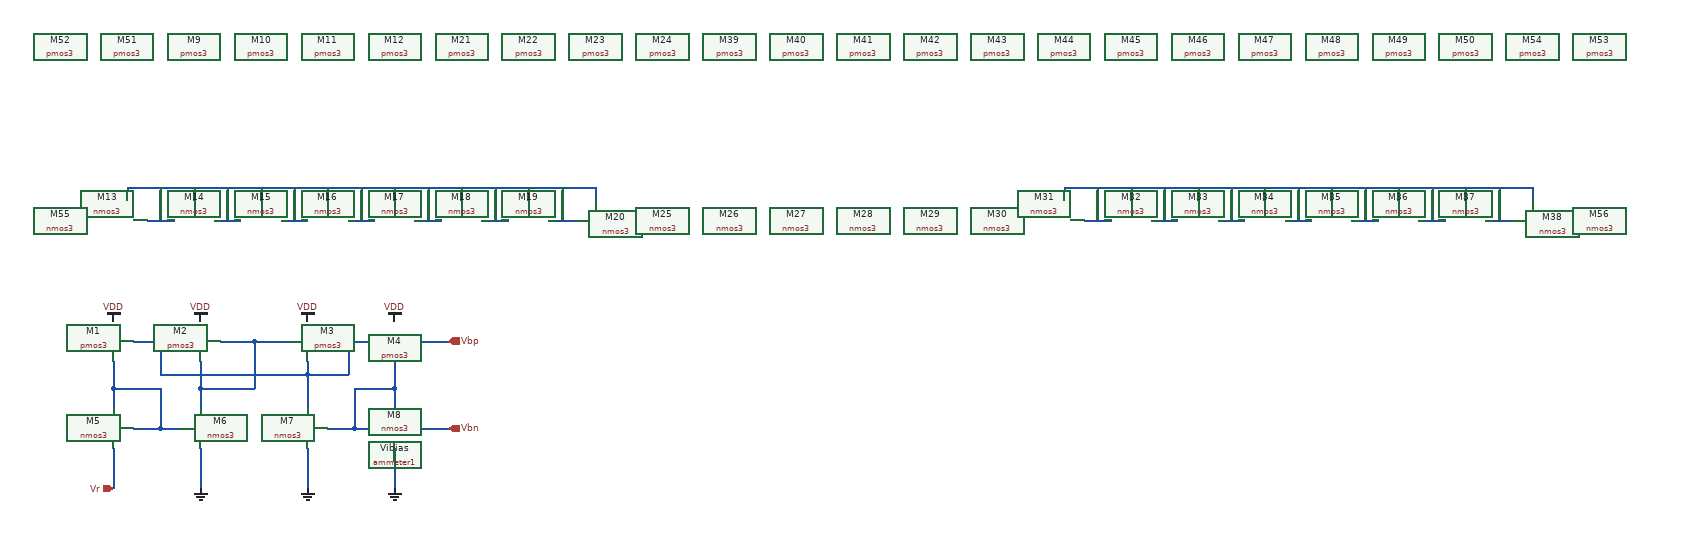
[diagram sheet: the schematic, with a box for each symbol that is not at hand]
v {xschem version=2.9.9 file_version=1.2 }
G {}
K {}
V {}
S {}
E {}
N 250 20 250 80 { lab=GND}
N 410 20 410 80 { lab=GND}
N 250 -70 250 -40 { lab=#net1}
N 410 -90 410 -40 { lab=Vbp}
N 330 -140 380 -140 { lab=#net1}
N 330 -140 330 -70 { lab=#net1}
N 250 -70 330 -70 { lab=#net1}
N 410 -90 470 -90 { lab=Vbp}
N 470 -140 470 -90 { lab=Vbp}
N 190 -90 410 -90 { lab=Vbp}
N 190 -140 190 -90 { lab=Vbp}
N 150 -140 190 -140 { lab=Vbp}
N 120 -70 120 -40 { lab=#net2}
N 190 -10 220 -10 { lab=#net2}
N 120 -70 190 -70 { lab=#net2}
N 190 -70 190 -10 { lab=#net2}
N 540 -70 540 -40 { lab=Vbn}
N 280 -140 330 -140 { lab=#net1}
N 250 -110 250 -70 { lab=#net1}
N 410 -110 410 -90 { lab=Vbp}
N 120 -110 120 -70 { lab=#net2}
N 150 -10 190 -10 { lab=#net2}
N 480 -70 540 -70 { lab=Vbn}
N 540 -110 540 -70 { lab=Vbn}
N 480 -70 480 -10 { lab=Vbn}
N 440 -10 480 -10 { lab=Vbn}
N 120 20 120 80 { lab=Vr}
N 480 -10 510 -10 { lab=Vbn}
N 510 -10 620 -10 { lab=Vbn}
N 470 -140 510 -140 { lab=Vbp}
N 510 -140 620 -140 { lab=Vbp}
N 540 50 540 80 { lab=GND}
N 540 20 540 40 { lab=#net3}
N 140 -370 140 -350 { lab=#net8}
N 140 -370 840 -370 { lab=#net8}
N 840 -370 840 -350 { lab=#net8}
N 170 -320 210 -320 { lab=#net8}
N 270 -320 310 -320 { lab=#net8}
N 370 -320 410 -320 { lab=#net8}
N 470 -320 510 -320 { lab=#net8}
N 570 -320 610 -320 { lab=#net8}
N 670 -320 710 -320 { lab=#net8}
N 770 -320 810 -320 { lab=#net8}
N 790 -370 790 -320 { lab=#net8}
N 740 -370 740 -350 { lab=#net8}
N 640 -370 640 -350 { lab=#net8}
N 540 -370 540 -350 { lab=#net8}
N 440 -370 440 -350 { lab=#net8}
N 340 -370 340 -350 { lab=#net8}
N 240 -370 240 -350 { lab=#net8}
N 190 -370 190 -320 { lab=#net8}
N 290 -370 290 -320 { lab=#net8}
N 390 -370 390 -320 { lab=#net8}
N 490 -370 490 -320 { lab=#net8}
N 590 -370 590 -320 { lab=#net8}
N 690 -370 690 -320 { lab=#net8}
N 1540 -370 1540 -350 { lab=#net9}
N 1540 -370 2240 -370 { lab=#net9}
N 2240 -370 2240 -350 { lab=#net9}
N 1570 -320 1610 -320 { lab=#net9}
N 1670 -320 1710 -320 { lab=#net9}
N 1770 -320 1810 -320 { lab=#net9}
N 1870 -320 1910 -320 { lab=#net9}
N 1970 -320 2010 -320 { lab=#net9}
N 2070 -320 2110 -320 { lab=#net9}
N 2170 -320 2210 -320 { lab=#net9}
N 2190 -370 2190 -320 { lab=#net9}
N 2140 -370 2140 -350 { lab=#net9}
N 2040 -370 2040 -350 { lab=#net9}
N 1940 -370 1940 -350 { lab=#net9}
N 1840 -370 1840 -350 { lab=#net9}
N 1740 -370 1740 -350 { lab=#net9}
N 1640 -370 1640 -350 { lab=#net9}
N 1590 -370 1590 -320 { lab=#net9}
N 1690 -370 1690 -320 { lab=#net9}
N 1790 -370 1790 -320 { lab=#net9}
N 1890 -370 1890 -320 { lab=#net9}
N 1990 -370 1990 -320 { lab=#net9}
N 2090 -370 2090 -320 { lab=#net9}
C {madvlsi/pmos3.sym} 120 -140 0 1 {name=M1
L=1.0
W=3
body=VDD
nf=1
mult=1
ad="'int((nf+1)/2) * W/nf * 0.29'" 
pd="'2*int((nf+1)/2) * (W/nf + 0.29)'"
as="'int((nf+2)/2) * W/nf * 0.29'" 
ps="'2*int((nf+2)/2) * (W/nf + 0.29)'"
nrd="'0.29 / W'" nrs="'0.29 / W'"
sa=0 sb=0 sd=0
model=pfet_01v8
spiceprefix=X
}
C {madvlsi/pmos3.sym} 250 -140 0 1 {name=M2
L=1.0
W=3
body=VDD
nf=1
mult=1
ad="'int((nf+1)/2) * W/nf * 0.29'" 
pd="'2*int((nf+1)/2) * (W/nf + 0.29)'"
as="'int((nf+2)/2) * W/nf * 0.29'" 
ps="'2*int((nf+2)/2) * (W/nf + 0.29)'"
nrd="'0.29 / W'" nrs="'0.29 / W'"
sa=0 sb=0 sd=0
model=pfet_01v8
spiceprefix=X
}
C {madvlsi/pmos3.sym} 410 -140 0 0 {name=M3
L=1.0
W=3
body=VDD
nf=1
mult=1
ad="'int((nf+1)/2) * W/nf * 0.29'" 
pd="'2*int((nf+1)/2) * (W/nf + 0.29)'"
as="'int((nf+2)/2) * W/nf * 0.29'" 
ps="'2*int((nf+2)/2) * (W/nf + 0.29)'"
nrd="'0.29 / W'" nrs="'0.29 / W'"
sa=0 sb=0 sd=0
model=pfet_01v8
spiceprefix=X
}
C {madvlsi/pmos3.sym} 540 -140 0 0 {name=M4
L=1.0
W=3
body=VDD
nf=1
mult=1
ad="'int((nf+1)/2) * W/nf * 0.29'" 
pd="'2*int((nf+1)/2) * (W/nf + 0.29)'"
as="'int((nf+2)/2) * W/nf * 0.29'" 
ps="'2*int((nf+2)/2) * (W/nf + 0.29)'"
nrd="'0.29 / W'" nrs="'0.29 / W'"
sa=0 sb=0 sd=0
model=pfet_01v8
spiceprefix=X
}
C {madvlsi/nmos3.sym} 120 -10 0 1 {name=M5
L=1.0
W=3
body=GND
nf=1
mult=8
ad="'int((nf+1)/2) * W/nf * 0.29'" 
pd="'2*int((nf+1)/2) * (W/nf + 0.29)'"
as="'int((nf+2)/2) * W/nf * 0.29'" 
ps="'2*int((nf+2)/2) * (W/nf + 0.29)'"
nrd="'0.29 / W'" nrs="'0.29 / W'"
sa=0 sb=0 sd=0
model=nfet_01v8
spiceprefix=X
}
C {madvlsi/nmos3.sym} 250 -10 0 0 {name=M6
L=1.0
W=3
body=GND
nf=1
mult=1
ad="'int((nf+1)/2) * W/nf * 0.29'" 
pd="'2*int((nf+1)/2) * (W/nf + 0.29)'"
as="'int((nf+2)/2) * W/nf * 0.29'" 
ps="'2*int((nf+2)/2) * (W/nf + 0.29)'"
nrd="'0.29 / W'" nrs="'0.29 / W'"
sa=0 sb=0 sd=0
model=nfet_01v8
spiceprefix=X
}
C {madvlsi/nmos3.sym} 410 -10 0 1 {name=M7
L=1.0
W=3
body=GND
nf=1
mult=1
ad="'int((nf+1)/2) * W/nf * 0.29'" 
pd="'2*int((nf+1)/2) * (W/nf + 0.29)'"
as="'int((nf+2)/2) * W/nf * 0.29'" 
ps="'2*int((nf+2)/2) * (W/nf + 0.29)'"
nrd="'0.29 / W'" nrs="'0.29 / W'"
sa=0 sb=0 sd=0
model=nfet_01v8
spiceprefix=X
}
C {madvlsi/nmos3.sym} 540 -10 0 0 {name=M8
L=1.0
W=3
body=GND
nf=1
mult=1
ad="'int((nf+1)/2) * W/nf * 0.29'" 
pd="'2*int((nf+1)/2) * (W/nf + 0.29)'"
as="'int((nf+2)/2) * W/nf * 0.29'" 
ps="'2*int((nf+2)/2) * (W/nf + 0.29)'"
nrd="'0.29 / W'" nrs="'0.29 / W'"
sa=0 sb=0 sd=0
model=nfet_01v8
spiceprefix=X
}
C {madvlsi/vdd.sym} 120 -170 0 0 {name=l1 lab=VDD}
C {madvlsi/vdd.sym} 250 -170 0 0 {name=l2 lab=VDD}
C {madvlsi/vdd.sym} 410 -170 0 0 {name=l3 lab=VDD}
C {madvlsi/vdd.sym} 540 -170 0 0 {name=l4 lab=VDD}
C {madvlsi/gnd.sym} 250 80 0 0 {name=l6 lab=GND}
C {madvlsi/gnd.sym} 410 80 0 0 {name=l7 lab=GND}
C {madvlsi/gnd.sym} 540 80 0 0 {name=l8 lab=GND}
C {devices/opin.sym} 620 -10 0 0 {name=p1 lab=Vbn}
C {devices/opin.sym} 620 -140 0 0 {name=p2 lab=Vbp}
C {devices/iopin.sym} 120 80 1 0 {name=p3 lab=Vr}
C {madvlsi/ammeter1.sym} 540 40 0 0 {name=Vibias}
C {madvlsi/pmos3.sym} 240 -580 1 1 {name=M9
L=1.0
W=3
body=VDD
nf=1
mult=1
ad="'int((nf+1)/2) * W/nf * 0.29'" 
pd="'2*int((nf+1)/2) * (W/nf + 0.29)'"
as="'int((nf+2)/2) * W/nf * 0.29'" 
ps="'2*int((nf+2)/2) * (W/nf + 0.29)'"
nrd="'0.29 / W'" nrs="'0.29 / W'"
sa=0 sb=0 sd=0
model=pfet_01v8
spiceprefix=X
}
C {madvlsi/pmos3.sym} 340 -580 1 1 {name=M10
L=1.0
W=3
body=VDD
nf=1
mult=1
ad="'int((nf+1)/2) * W/nf * 0.29'" 
pd="'2*int((nf+1)/2) * (W/nf + 0.29)'"
as="'int((nf+2)/2) * W/nf * 0.29'" 
ps="'2*int((nf+2)/2) * (W/nf + 0.29)'"
nrd="'0.29 / W'" nrs="'0.29 / W'"
sa=0 sb=0 sd=0
model=pfet_01v8
spiceprefix=X
}
C {madvlsi/pmos3.sym} 440 -580 1 1 {name=M11
L=1.0
W=3
body=VDD
nf=1
mult=1
ad="'int((nf+1)/2) * W/nf * 0.29'" 
pd="'2*int((nf+1)/2) * (W/nf + 0.29)'"
as="'int((nf+2)/2) * W/nf * 0.29'" 
ps="'2*int((nf+2)/2) * (W/nf + 0.29)'"
nrd="'0.29 / W'" nrs="'0.29 / W'"
sa=0 sb=0 sd=0
model=pfet_01v8
spiceprefix=X
}
C {madvlsi/pmos3.sym} 540 -580 1 1 {name=M12
L=1.0
W=3
body=VDD
nf=1
mult=1
ad="'int((nf+1)/2) * W/nf * 0.29'" 
pd="'2*int((nf+1)/2) * (W/nf + 0.29)'"
as="'int((nf+2)/2) * W/nf * 0.29'" 
ps="'2*int((nf+2)/2) * (W/nf + 0.29)'"
nrd="'0.29 / W'" nrs="'0.29 / W'"
sa=0 sb=0 sd=0
model=pfet_01v8
spiceprefix=X
}
C {madvlsi/nmos3.sym} 140 -320 1 0 {name=M13
L=1.0
W=3
body=GND
nf=1
mult=1
ad="'int((nf+1)/2) * W/nf * 0.29'" 
pd="'2*int((nf+1)/2) * (W/nf + 0.29)'"
as="'int((nf+2)/2) * W/nf * 0.29'" 
ps="'2*int((nf+2)/2) * (W/nf + 0.29)'"
nrd="'0.29 / W'" nrs="'0.29 / W'"
sa=0 sb=0 sd=0
model=nfet_01v8
spiceprefix=X
}
C {madvlsi/nmos3.sym} 240 -320 1 0 {name=M14
L=1.0
W=3
body=GND
nf=1
mult=1
ad="'int((nf+1)/2) * W/nf * 0.29'" 
pd="'2*int((nf+1)/2) * (W/nf + 0.29)'"
as="'int((nf+2)/2) * W/nf * 0.29'" 
ps="'2*int((nf+2)/2) * (W/nf + 0.29)'"
nrd="'0.29 / W'" nrs="'0.29 / W'"
sa=0 sb=0 sd=0
model=nfet_01v8
spiceprefix=X
}
C {madvlsi/nmos3.sym} 340 -320 1 0 {name=M15
L=1.0
W=3
body=GND
nf=1
mult=1
ad="'int((nf+1)/2) * W/nf * 0.29'" 
pd="'2*int((nf+1)/2) * (W/nf + 0.29)'"
as="'int((nf+2)/2) * W/nf * 0.29'" 
ps="'2*int((nf+2)/2) * (W/nf + 0.29)'"
nrd="'0.29 / W'" nrs="'0.29 / W'"
sa=0 sb=0 sd=0
model=nfet_01v8
spiceprefix=X
}
C {madvlsi/nmos3.sym} 440 -320 1 0 {name=M16
L=1.0
W=3
body=GND
nf=1
mult=1
ad="'int((nf+1)/2) * W/nf * 0.29'" 
pd="'2*int((nf+1)/2) * (W/nf + 0.29)'"
as="'int((nf+2)/2) * W/nf * 0.29'" 
ps="'2*int((nf+2)/2) * (W/nf + 0.29)'"
nrd="'0.29 / W'" nrs="'0.29 / W'"
sa=0 sb=0 sd=0
model=nfet_01v8
spiceprefix=X
}
C {madvlsi/nmos3.sym} 540 -320 1 0 {name=M17
L=1.0
W=3
body=GND
nf=1
mult=1
ad="'int((nf+1)/2) * W/nf * 0.29'" 
pd="'2*int((nf+1)/2) * (W/nf + 0.29)'"
as="'int((nf+2)/2) * W/nf * 0.29'" 
ps="'2*int((nf+2)/2) * (W/nf + 0.29)'"
nrd="'0.29 / W'" nrs="'0.29 / W'"
sa=0 sb=0 sd=0
model=nfet_01v8
spiceprefix=X
}
C {madvlsi/nmos3.sym} 640 -320 1 0 {name=M18
L=1.0
W=3
body=GND
nf=1
mult=1
ad="'int((nf+1)/2) * W/nf * 0.29'" 
pd="'2*int((nf+1)/2) * (W/nf + 0.29)'"
as="'int((nf+2)/2) * W/nf * 0.29'" 
ps="'2*int((nf+2)/2) * (W/nf + 0.29)'"
nrd="'0.29 / W'" nrs="'0.29 / W'"
sa=0 sb=0 sd=0
model=nfet_01v8
spiceprefix=X
}
C {madvlsi/nmos3.sym} 740 -320 1 0 {name=M19
L=1.0
W=3
body=GND
nf=1
mult=1
ad="'int((nf+1)/2) * W/nf * 0.29'" 
pd="'2*int((nf+1)/2) * (W/nf + 0.29)'"
as="'int((nf+2)/2) * W/nf * 0.29'" 
ps="'2*int((nf+2)/2) * (W/nf + 0.29)'"
nrd="'0.29 / W'" nrs="'0.29 / W'"
sa=0 sb=0 sd=0
model=nfet_01v8
spiceprefix=X
}
C {madvlsi/nmos3.sym} 840 -320 1 0 {name=M20
L=1.0
W=3
body=GND
nf=1
mult=1
ad="'int((nf+1)/2) * W/nf * 0.29'" 
pd="'2*int((nf+1)/2) * (W/nf + 0.29)'"
as="'int((nf+2)/2) * W/nf * 0.29'" 
ps="'2*int((nf+2)/2) * (W/nf + 0.29)'"
nrd="'0.29 / W'" nrs="'0.29 / W'"
sa=0 sb=0 sd=0
model=nfet_01v8
spiceprefix=X
}
C {madvlsi/pmos3.sym} 640 -580 1 1 {name=M21
L=1.0
W=3
body=VDD
nf=1
mult=1
ad="'int((nf+1)/2) * W/nf * 0.29'" 
pd="'2*int((nf+1)/2) * (W/nf + 0.29)'"
as="'int((nf+2)/2) * W/nf * 0.29'" 
ps="'2*int((nf+2)/2) * (W/nf + 0.29)'"
nrd="'0.29 / W'" nrs="'0.29 / W'"
sa=0 sb=0 sd=0
model=pfet_01v8
spiceprefix=X
}
C {madvlsi/pmos3.sym} 740 -580 1 1 {name=M22
L=1.0
W=3
body=VDD
nf=1
mult=1
ad="'int((nf+1)/2) * W/nf * 0.29'" 
pd="'2*int((nf+1)/2) * (W/nf + 0.29)'"
as="'int((nf+2)/2) * W/nf * 0.29'" 
ps="'2*int((nf+2)/2) * (W/nf + 0.29)'"
nrd="'0.29 / W'" nrs="'0.29 / W'"
sa=0 sb=0 sd=0
model=pfet_01v8
spiceprefix=X
}
C {madvlsi/pmos3.sym} 840 -580 1 1 {name=M23
L=1.0
W=3
body=VDD
nf=1
mult=1
ad="'int((nf+1)/2) * W/nf * 0.29'" 
pd="'2*int((nf+1)/2) * (W/nf + 0.29)'"
as="'int((nf+2)/2) * W/nf * 0.29'" 
ps="'2*int((nf+2)/2) * (W/nf + 0.29)'"
nrd="'0.29 / W'" nrs="'0.29 / W'"
sa=0 sb=0 sd=0
model=pfet_01v8
spiceprefix=X
}
C {madvlsi/pmos3.sym} 940 -580 1 1 {name=M24
L=1.0
W=3
body=VDD
nf=1
mult=1
ad="'int((nf+1)/2) * W/nf * 0.29'" 
pd="'2*int((nf+1)/2) * (W/nf + 0.29)'"
as="'int((nf+2)/2) * W/nf * 0.29'" 
ps="'2*int((nf+2)/2) * (W/nf + 0.29)'"
nrd="'0.29 / W'" nrs="'0.29 / W'"
sa=0 sb=0 sd=0
model=pfet_01v8
spiceprefix=X
}
C {madvlsi/nmos3.sym} 940 -320 1 0 {name=M25
L=1.0
W=3
body=GND
nf=1
mult=1
ad="'int((nf+1)/2) * W/nf * 0.29'" 
pd="'2*int((nf+1)/2) * (W/nf + 0.29)'"
as="'int((nf+2)/2) * W/nf * 0.29'" 
ps="'2*int((nf+2)/2) * (W/nf + 0.29)'"
nrd="'0.29 / W'" nrs="'0.29 / W'"
sa=0 sb=0 sd=0
model=nfet_01v8
spiceprefix=X
}
C {madvlsi/nmos3.sym} 1040 -320 1 0 {name=M26
L=1.0
W=3
body=GND
nf=1
mult=1
ad="'int((nf+1)/2) * W/nf * 0.29'" 
pd="'2*int((nf+1)/2) * (W/nf + 0.29)'"
as="'int((nf+2)/2) * W/nf * 0.29'" 
ps="'2*int((nf+2)/2) * (W/nf + 0.29)'"
nrd="'0.29 / W'" nrs="'0.29 / W'"
sa=0 sb=0 sd=0
model=nfet_01v8
spiceprefix=X
}
C {madvlsi/nmos3.sym} 1140 -320 1 0 {name=M27
L=1.0
W=3
body=GND
nf=1
mult=1
ad="'int((nf+1)/2) * W/nf * 0.29'" 
pd="'2*int((nf+1)/2) * (W/nf + 0.29)'"
as="'int((nf+2)/2) * W/nf * 0.29'" 
ps="'2*int((nf+2)/2) * (W/nf + 0.29)'"
nrd="'0.29 / W'" nrs="'0.29 / W'"
sa=0 sb=0 sd=0
model=nfet_01v8
spiceprefix=X
}
C {madvlsi/nmos3.sym} 1240 -320 1 0 {name=M28
L=1.0
W=3
body=GND
nf=1
mult=1
ad="'int((nf+1)/2) * W/nf * 0.29'" 
pd="'2*int((nf+1)/2) * (W/nf + 0.29)'"
as="'int((nf+2)/2) * W/nf * 0.29'" 
ps="'2*int((nf+2)/2) * (W/nf + 0.29)'"
nrd="'0.29 / W'" nrs="'0.29 / W'"
sa=0 sb=0 sd=0
model=nfet_01v8
spiceprefix=X
}
C {madvlsi/nmos3.sym} 1340 -320 1 0 {name=M29
L=1.0
W=3
body=GND
nf=1
mult=1
ad="'int((nf+1)/2) * W/nf * 0.29'" 
pd="'2*int((nf+1)/2) * (W/nf + 0.29)'"
as="'int((nf+2)/2) * W/nf * 0.29'" 
ps="'2*int((nf+2)/2) * (W/nf + 0.29)'"
nrd="'0.29 / W'" nrs="'0.29 / W'"
sa=0 sb=0 sd=0
model=nfet_01v8
spiceprefix=X
}
C {madvlsi/nmos3.sym} 1440 -320 1 0 {name=M30
L=1.0
W=3
body=GND
nf=1
mult=1
ad="'int((nf+1)/2) * W/nf * 0.29'" 
pd="'2*int((nf+1)/2) * (W/nf + 0.29)'"
as="'int((nf+2)/2) * W/nf * 0.29'" 
ps="'2*int((nf+2)/2) * (W/nf + 0.29)'"
nrd="'0.29 / W'" nrs="'0.29 / W'"
sa=0 sb=0 sd=0
model=nfet_01v8
spiceprefix=X
}
C {madvlsi/nmos3.sym} 1540 -320 1 0 {name=M31
L=1.0
W=3
body=GND
nf=1
mult=1
ad="'int((nf+1)/2) * W/nf * 0.29'" 
pd="'2*int((nf+1)/2) * (W/nf + 0.29)'"
as="'int((nf+2)/2) * W/nf * 0.29'" 
ps="'2*int((nf+2)/2) * (W/nf + 0.29)'"
nrd="'0.29 / W'" nrs="'0.29 / W'"
sa=0 sb=0 sd=0
model=nfet_01v8
spiceprefix=X
}
C {madvlsi/nmos3.sym} 1640 -320 1 0 {name=M32
L=1.0
W=3
body=GND
nf=1
mult=1
ad="'int((nf+1)/2) * W/nf * 0.29'" 
pd="'2*int((nf+1)/2) * (W/nf + 0.29)'"
as="'int((nf+2)/2) * W/nf * 0.29'" 
ps="'2*int((nf+2)/2) * (W/nf + 0.29)'"
nrd="'0.29 / W'" nrs="'0.29 / W'"
sa=0 sb=0 sd=0
model=nfet_01v8
spiceprefix=X
}
C {madvlsi/nmos3.sym} 1740 -320 1 0 {name=M33
L=1.0
W=3
body=GND
nf=1
mult=1
ad="'int((nf+1)/2) * W/nf * 0.29'" 
pd="'2*int((nf+1)/2) * (W/nf + 0.29)'"
as="'int((nf+2)/2) * W/nf * 0.29'" 
ps="'2*int((nf+2)/2) * (W/nf + 0.29)'"
nrd="'0.29 / W'" nrs="'0.29 / W'"
sa=0 sb=0 sd=0
model=nfet_01v8
spiceprefix=X
}
C {madvlsi/nmos3.sym} 1840 -320 1 0 {name=M34
L=1.0
W=3
body=GND
nf=1
mult=1
ad="'int((nf+1)/2) * W/nf * 0.29'" 
pd="'2*int((nf+1)/2) * (W/nf + 0.29)'"
as="'int((nf+2)/2) * W/nf * 0.29'" 
ps="'2*int((nf+2)/2) * (W/nf + 0.29)'"
nrd="'0.29 / W'" nrs="'0.29 / W'"
sa=0 sb=0 sd=0
model=nfet_01v8
spiceprefix=X
}
C {madvlsi/nmos3.sym} 1940 -320 1 0 {name=M35
L=1.0
W=3
body=GND
nf=1
mult=1
ad="'int((nf+1)/2) * W/nf * 0.29'" 
pd="'2*int((nf+1)/2) * (W/nf + 0.29)'"
as="'int((nf+2)/2) * W/nf * 0.29'" 
ps="'2*int((nf+2)/2) * (W/nf + 0.29)'"
nrd="'0.29 / W'" nrs="'0.29 / W'"
sa=0 sb=0 sd=0
model=nfet_01v8
spiceprefix=X
}
C {madvlsi/nmos3.sym} 2040 -320 1 0 {name=M36
L=1.0
W=3
body=GND
nf=1
mult=1
ad="'int((nf+1)/2) * W/nf * 0.29'" 
pd="'2*int((nf+1)/2) * (W/nf + 0.29)'"
as="'int((nf+2)/2) * W/nf * 0.29'" 
ps="'2*int((nf+2)/2) * (W/nf + 0.29)'"
nrd="'0.29 / W'" nrs="'0.29 / W'"
sa=0 sb=0 sd=0
model=nfet_01v8
spiceprefix=X
}
C {madvlsi/nmos3.sym} 2140 -320 1 0 {name=M37
L=1.0
W=3
body=GND
nf=1
mult=1
ad="'int((nf+1)/2) * W/nf * 0.29'" 
pd="'2*int((nf+1)/2) * (W/nf + 0.29)'"
as="'int((nf+2)/2) * W/nf * 0.29'" 
ps="'2*int((nf+2)/2) * (W/nf + 0.29)'"
nrd="'0.29 / W'" nrs="'0.29 / W'"
sa=0 sb=0 sd=0
model=nfet_01v8
spiceprefix=X
}
C {madvlsi/nmos3.sym} 2240 -320 1 0 {name=M38
L=1.0
W=3
body=GND
nf=1
mult=1
ad="'int((nf+1)/2) * W/nf * 0.29'" 
pd="'2*int((nf+1)/2) * (W/nf + 0.29)'"
as="'int((nf+2)/2) * W/nf * 0.29'" 
ps="'2*int((nf+2)/2) * (W/nf + 0.29)'"
nrd="'0.29 / W'" nrs="'0.29 / W'"
sa=0 sb=0 sd=0
model=nfet_01v8
spiceprefix=X
}
C {madvlsi/pmos3.sym} 1040 -580 1 1 {name=M39
L=1.0
W=3
body=VDD
nf=1
mult=1
ad="'int((nf+1)/2) * W/nf * 0.29'" 
pd="'2*int((nf+1)/2) * (W/nf + 0.29)'"
as="'int((nf+2)/2) * W/nf * 0.29'" 
ps="'2*int((nf+2)/2) * (W/nf + 0.29)'"
nrd="'0.29 / W'" nrs="'0.29 / W'"
sa=0 sb=0 sd=0
model=pfet_01v8
spiceprefix=X
}
C {madvlsi/pmos3.sym} 1140 -580 1 1 {name=M40
L=1.0
W=3
body=VDD
nf=1
mult=1
ad="'int((nf+1)/2) * W/nf * 0.29'" 
pd="'2*int((nf+1)/2) * (W/nf + 0.29)'"
as="'int((nf+2)/2) * W/nf * 0.29'" 
ps="'2*int((nf+2)/2) * (W/nf + 0.29)'"
nrd="'0.29 / W'" nrs="'0.29 / W'"
sa=0 sb=0 sd=0
model=pfet_01v8
spiceprefix=X
}
C {madvlsi/pmos3.sym} 1240 -580 1 1 {name=M41
L=1.0
W=3
body=VDD
nf=1
mult=1
ad="'int((nf+1)/2) * W/nf * 0.29'" 
pd="'2*int((nf+1)/2) * (W/nf + 0.29)'"
as="'int((nf+2)/2) * W/nf * 0.29'" 
ps="'2*int((nf+2)/2) * (W/nf + 0.29)'"
nrd="'0.29 / W'" nrs="'0.29 / W'"
sa=0 sb=0 sd=0
model=pfet_01v8
spiceprefix=X
}
C {madvlsi/pmos3.sym} 1340 -580 1 1 {name=M42
L=1.0
W=3
body=VDD
nf=1
mult=1
ad="'int((nf+1)/2) * W/nf * 0.29'" 
pd="'2*int((nf+1)/2) * (W/nf + 0.29)'"
as="'int((nf+2)/2) * W/nf * 0.29'" 
ps="'2*int((nf+2)/2) * (W/nf + 0.29)'"
nrd="'0.29 / W'" nrs="'0.29 / W'"
sa=0 sb=0 sd=0
model=pfet_01v8
spiceprefix=X
}
C {madvlsi/pmos3.sym} 1440 -580 1 1 {name=M43
L=1.0
W=3
body=VDD
nf=1
mult=1
ad="'int((nf+1)/2) * W/nf * 0.29'" 
pd="'2*int((nf+1)/2) * (W/nf + 0.29)'"
as="'int((nf+2)/2) * W/nf * 0.29'" 
ps="'2*int((nf+2)/2) * (W/nf + 0.29)'"
nrd="'0.29 / W'" nrs="'0.29 / W'"
sa=0 sb=0 sd=0
model=pfet_01v8
spiceprefix=X
}
C {madvlsi/pmos3.sym} 1540 -580 1 1 {name=M44
L=1.0
W=3
body=VDD
nf=1
mult=1
ad="'int((nf+1)/2) * W/nf * 0.29'" 
pd="'2*int((nf+1)/2) * (W/nf + 0.29)'"
as="'int((nf+2)/2) * W/nf * 0.29'" 
ps="'2*int((nf+2)/2) * (W/nf + 0.29)'"
nrd="'0.29 / W'" nrs="'0.29 / W'"
sa=0 sb=0 sd=0
model=pfet_01v8
spiceprefix=X
}
C {madvlsi/pmos3.sym} 1640 -580 1 1 {name=M45
L=1.0
W=3
body=VDD
nf=1
mult=1
ad="'int((nf+1)/2) * W/nf * 0.29'" 
pd="'2*int((nf+1)/2) * (W/nf + 0.29)'"
as="'int((nf+2)/2) * W/nf * 0.29'" 
ps="'2*int((nf+2)/2) * (W/nf + 0.29)'"
nrd="'0.29 / W'" nrs="'0.29 / W'"
sa=0 sb=0 sd=0
model=pfet_01v8
spiceprefix=X
}
C {madvlsi/pmos3.sym} 1740 -580 1 1 {name=M46
L=1.0
W=3
body=VDD
nf=1
mult=1
ad="'int((nf+1)/2) * W/nf * 0.29'" 
pd="'2*int((nf+1)/2) * (W/nf + 0.29)'"
as="'int((nf+2)/2) * W/nf * 0.29'" 
ps="'2*int((nf+2)/2) * (W/nf + 0.29)'"
nrd="'0.29 / W'" nrs="'0.29 / W'"
sa=0 sb=0 sd=0
model=pfet_01v8
spiceprefix=X
}
C {madvlsi/pmos3.sym} 1840 -580 1 1 {name=M47
L=1.0
W=3
body=VDD
nf=1
mult=1
ad="'int((nf+1)/2) * W/nf * 0.29'" 
pd="'2*int((nf+1)/2) * (W/nf + 0.29)'"
as="'int((nf+2)/2) * W/nf * 0.29'" 
ps="'2*int((nf+2)/2) * (W/nf + 0.29)'"
nrd="'0.29 / W'" nrs="'0.29 / W'"
sa=0 sb=0 sd=0
model=pfet_01v8
spiceprefix=X
}
C {madvlsi/pmos3.sym} 1940 -580 1 1 {name=M48
L=1.0
W=3
body=VDD
nf=1
mult=1
ad="'int((nf+1)/2) * W/nf * 0.29'" 
pd="'2*int((nf+1)/2) * (W/nf + 0.29)'"
as="'int((nf+2)/2) * W/nf * 0.29'" 
ps="'2*int((nf+2)/2) * (W/nf + 0.29)'"
nrd="'0.29 / W'" nrs="'0.29 / W'"
sa=0 sb=0 sd=0
model=pfet_01v8
spiceprefix=X
}
C {madvlsi/pmos3.sym} 2040 -580 1 1 {name=M49
L=1.0
W=3
body=VDD
nf=1
mult=1
ad="'int((nf+1)/2) * W/nf * 0.29'" 
pd="'2*int((nf+1)/2) * (W/nf + 0.29)'"
as="'int((nf+2)/2) * W/nf * 0.29'" 
ps="'2*int((nf+2)/2) * (W/nf + 0.29)'"
nrd="'0.29 / W'" nrs="'0.29 / W'"
sa=0 sb=0 sd=0
model=pfet_01v8
spiceprefix=X
}
C {madvlsi/pmos3.sym} 2140 -580 1 1 {name=M50
L=1.0
W=3
body=VDD
nf=1
mult=1
ad="'int((nf+1)/2) * W/nf * 0.29'" 
pd="'2*int((nf+1)/2) * (W/nf + 0.29)'"
as="'int((nf+2)/2) * W/nf * 0.29'" 
ps="'2*int((nf+2)/2) * (W/nf + 0.29)'"
nrd="'0.29 / W'" nrs="'0.29 / W'"
sa=0 sb=0 sd=0
model=pfet_01v8
spiceprefix=X
}
C {madvlsi/pmos3.sym} 140 -580 1 1 {name=M51
L=1.0
W=3
body=VDD
nf=1
mult=1
ad="'int((nf+1)/2) * W/nf * 0.29'" 
pd="'2*int((nf+1)/2) * (W/nf + 0.29)'"
as="'int((nf+2)/2) * W/nf * 0.29'" 
ps="'2*int((nf+2)/2) * (W/nf + 0.29)'"
nrd="'0.29 / W'" nrs="'0.29 / W'"
sa=0 sb=0 sd=0
model=pfet_01v8
spiceprefix=X
}
C {madvlsi/pmos3.sym} 40 -580 1 1 {name=M52
L=1.0
W=3
body=VDD
nf=1
mult=1
ad="'int((nf+1)/2) * W/nf * 0.29'" 
pd="'2*int((nf+1)/2) * (W/nf + 0.29)'"
as="'int((nf+2)/2) * W/nf * 0.29'" 
ps="'2*int((nf+2)/2) * (W/nf + 0.29)'"
nrd="'0.29 / W'" nrs="'0.29 / W'"
sa=0 sb=0 sd=0
model=pfet_01v8
spiceprefix=X
}
C {madvlsi/pmos3.sym} 2340 -580 1 1 {name=M53
L=1.0
W=3
body=VDD
nf=1
mult=1
ad="'int((nf+1)/2) * W/nf * 0.29'" 
pd="'2*int((nf+1)/2) * (W/nf + 0.29)'"
as="'int((nf+2)/2) * W/nf * 0.29'" 
ps="'2*int((nf+2)/2) * (W/nf + 0.29)'"
nrd="'0.29 / W'" nrs="'0.29 / W'"
sa=0 sb=0 sd=0
model=pfet_01v8
spiceprefix=X
}
C {madvlsi/pmos3.sym} 2240 -580 1 1 {name=M54
L=1.0
W=3
body=VDD
nf=1
mult=1
ad="'int((nf+1)/2) * W/nf * 0.29'" 
pd="'2*int((nf+1)/2) * (W/nf + 0.29)'"
as="'int((nf+2)/2) * W/nf * 0.29'" 
ps="'2*int((nf+2)/2) * (W/nf + 0.29)'"
nrd="'0.29 / W'" nrs="'0.29 / W'"
sa=0 sb=0 sd=0
model=pfet_01v8
spiceprefix=X
}
C {madvlsi/nmos3.sym} 40 -320 1 0 {name=M55
L=1.0
W=3
body=GND
nf=1
mult=1
ad="'int((nf+1)/2) * W/nf * 0.29'" 
pd="'2*int((nf+1)/2) * (W/nf + 0.29)'"
as="'int((nf+2)/2) * W/nf * 0.29'" 
ps="'2*int((nf+2)/2) * (W/nf + 0.29)'"
nrd="'0.29 / W'" nrs="'0.29 / W'"
sa=0 sb=0 sd=0
model=nfet_01v8
spiceprefix=X
}
C {madvlsi/nmos3.sym} 2340 -320 1 0 {name=M56
L=1.0
W=3
body=GND
nf=1
mult=1
ad="'int((nf+1)/2) * W/nf * 0.29'" 
pd="'2*int((nf+1)/2) * (W/nf + 0.29)'"
as="'int((nf+2)/2) * W/nf * 0.29'" 
ps="'2*int((nf+2)/2) * (W/nf + 0.29)'"
nrd="'0.29 / W'" nrs="'0.29 / W'"
sa=0 sb=0 sd=0
model=nfet_01v8
spiceprefix=X
}
